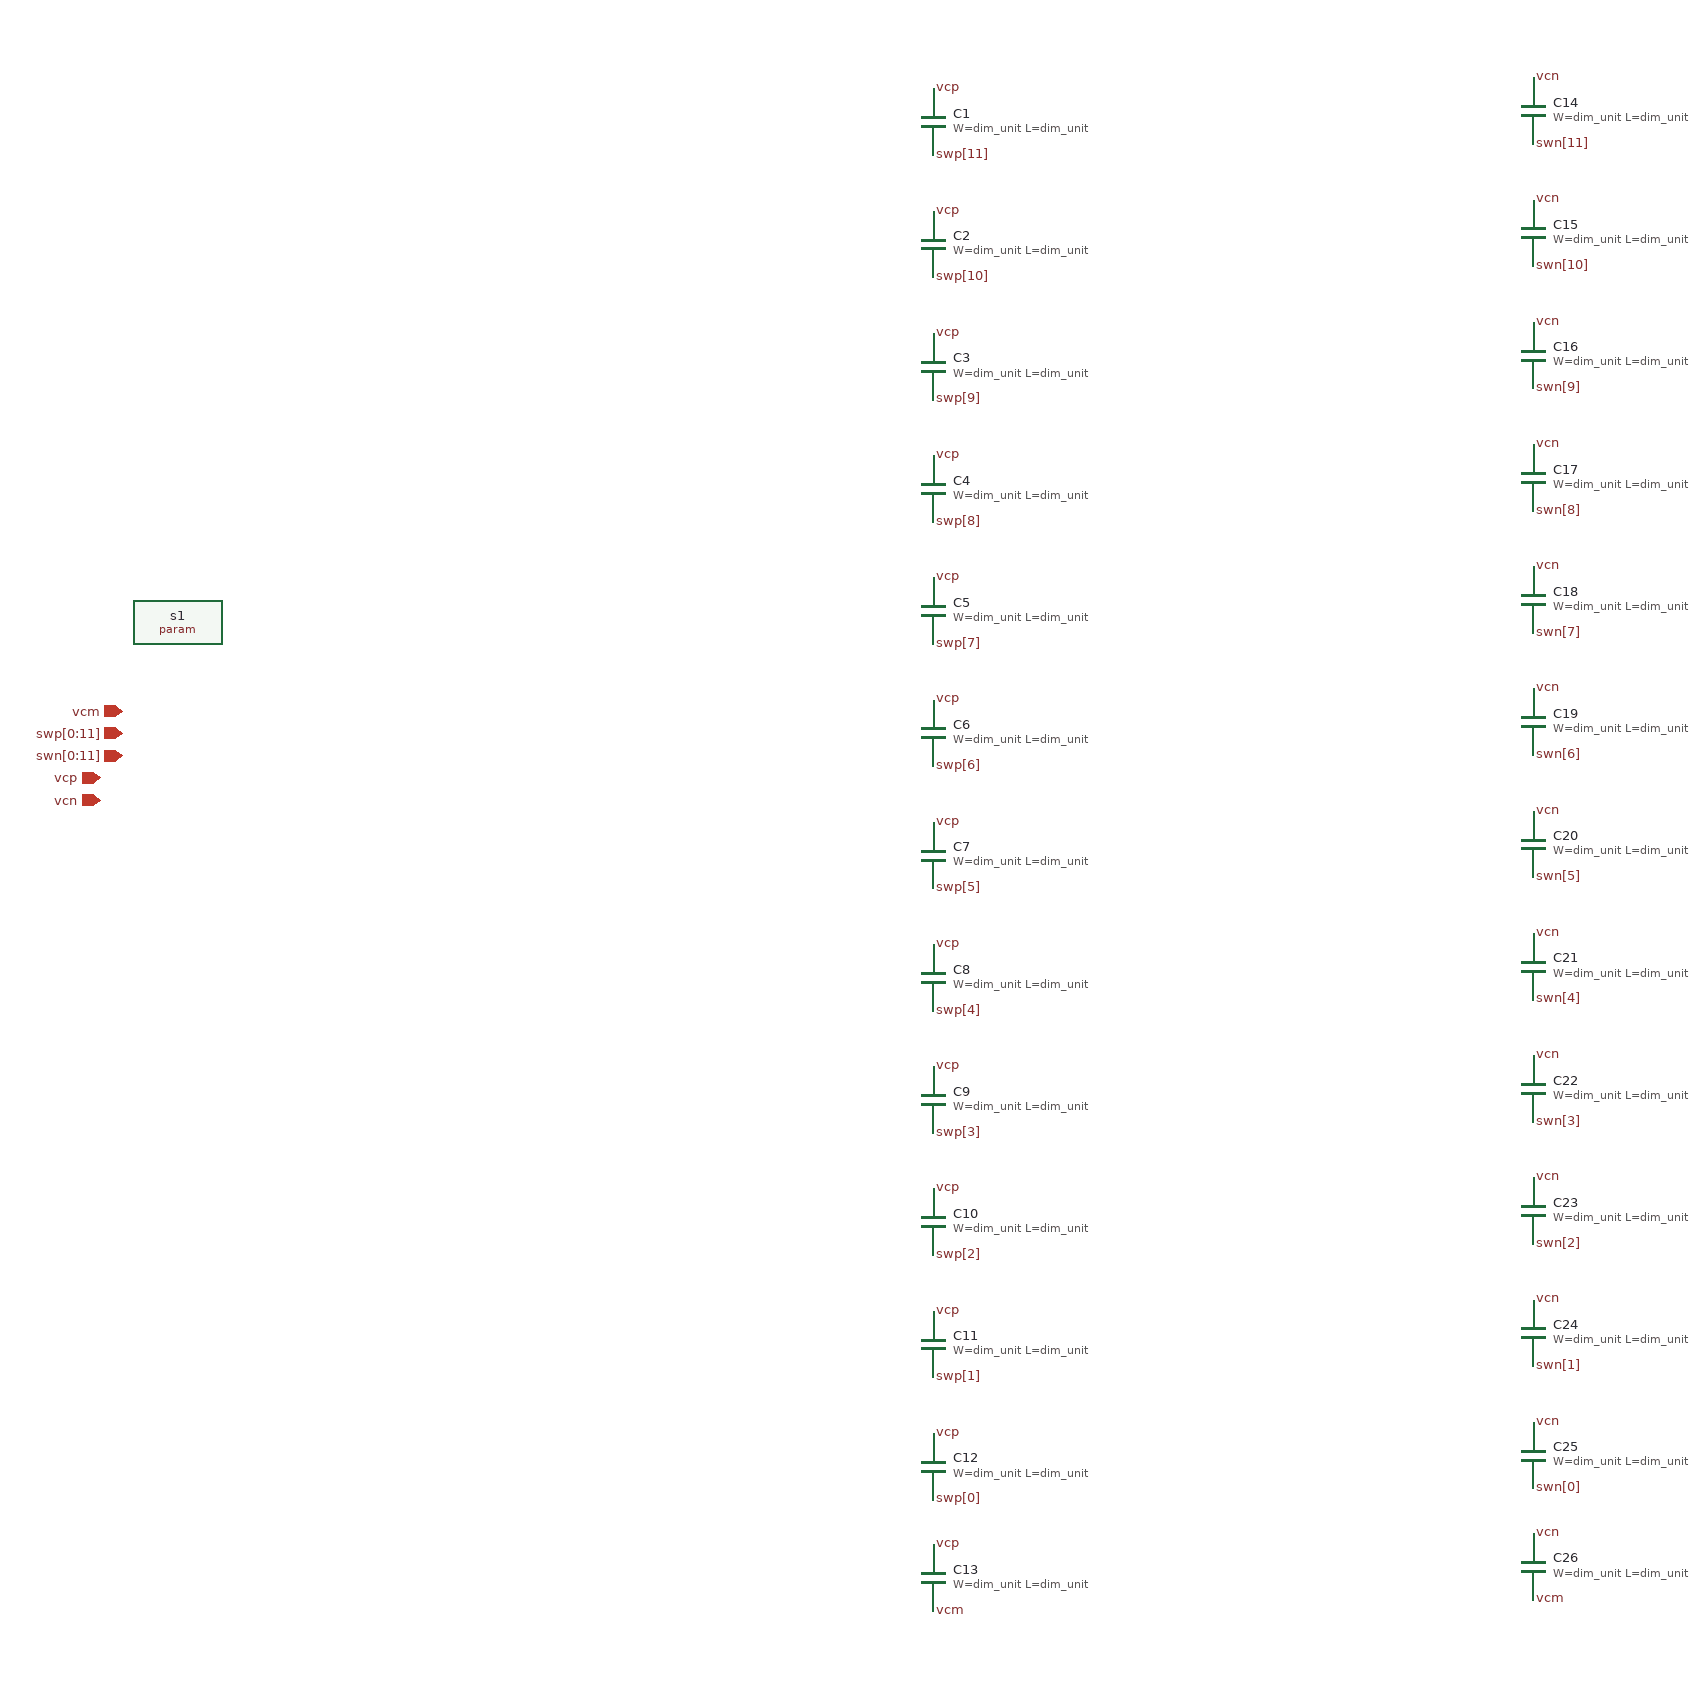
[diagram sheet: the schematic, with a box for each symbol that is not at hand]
v {xschem version=3.4.5 file_version=1.2
}
G {}
K {}
V {}
S {}
E {}
C {devices/lab_wire.sym} 950 -70 2 0 {name=p1 sig_type=std_logic lab=vcm}
C {devices/lab_wire.sym} 950 -170 2 0 {name=p3 sig_type=std_logic lab=swp[0]}
C {devices/lab_wire.sym} 1490 -180 2 0 {name=p4 sig_type=std_logic lab=swn[0]}
C {devices/lab_wire.sym} 950 -280 2 0 {name=p5 sig_type=std_logic lab=swp[1]}
C {devices/lab_wire.sym} 1490 -290 2 0 {name=p6 sig_type=std_logic lab=swn[1]}
C {devices/lab_wire.sym} 950 -390 2 0 {name=p7 sig_type=std_logic lab=swp[2]}
C {devices/lab_wire.sym} 1490 -400 2 0 {name=p8 sig_type=std_logic lab=swn[2]}
C {devices/lab_wire.sym} 950 -500 2 0 {name=p9 sig_type=std_logic lab=swp[3]}
C {devices/lab_wire.sym} 1490 -510 2 0 {name=p10 sig_type=std_logic lab=swn[3]}
C {devices/lab_wire.sym} 950 -610 2 0 {name=p11 sig_type=std_logic lab=swp[4]}
C {devices/lab_wire.sym} 1490 -620 2 0 {name=p12 sig_type=std_logic lab=swn[4]}
C {devices/lab_wire.sym} 950 -720 2 0 {name=p13 sig_type=std_logic lab=swp[5]}
C {devices/lab_wire.sym} 1490 -730 2 0 {name=p14 sig_type=std_logic lab=swn[5]}
C {devices/lab_wire.sym} 950 -830 2 0 {name=p15 sig_type=std_logic lab=swp[6]}
C {devices/lab_wire.sym} 1490 -840 2 0 {name=p16 sig_type=std_logic lab=swn[6]}
C {devices/lab_wire.sym} 950 -940 2 0 {name=p17 sig_type=std_logic lab=swp[7]}
C {devices/lab_wire.sym} 1490 -950 2 0 {name=p18 sig_type=std_logic lab=swn[7]}
C {devices/lab_wire.sym} 950 -1050 2 0 {name=p19 sig_type=std_logic lab=swp[8]}
C {devices/lab_wire.sym} 1490 -1060 2 0 {name=p20 sig_type=std_logic lab=swn[8]}
C {devices/lab_wire.sym} 950 -1160 2 0 {name=p21 sig_type=std_logic lab=swp[9]}
C {devices/lab_wire.sym} 1490 -1170 2 0 {name=p22 sig_type=std_logic lab=swn[9]}
C {devices/lab_wire.sym} 950 -1270 2 0 {name=p23 sig_type=std_logic lab=swp[10]}
C {devices/lab_wire.sym} 1490 -1280 2 0 {name=p24 sig_type=std_logic lab=swn[10]}
C {devices/lab_wire.sym} 950 -1380 2 0 {name=p25 sig_type=std_logic lab=swp[11]}
C {devices/lab_wire.sym} 1490 -1390 2 0 {name=p26 sig_type=std_logic lab=swn[11]}
C {devices/lab_wire.sym} 950 -1440 0 1 {name=p27 sig_type=std_logic lab=vcp}
C {devices/ipin.sym} 220 -860 0 0 {name=p53 lab=swp[0:11]}
C {devices/ipin.sym} 220 -880 0 0 {name=p54 lab=vcm}
C {devices/ipin.sym} 220 -840 0 0 {name=p55 lab=swn[0:11]}
C {devices/iopin.sym} 200 -820 0 0 {name=p56 lab=vcp}
C {devices/iopin.sym} 200 -800 0 0 {name=p57 lab=vcn}
C {devices/param.sym} 270 -960 0 0 {name=s1 value="dim_unit=2u"}
C {sky130_fd_pr/cap_mim_m3_1.sym} 950 -1410 0 0 {name=C1 model=cap_mim_m3_1 W=dim_unit L=dim_unit MF=2048 spiceprefix=X}
C {devices/lab_wire.sym} 950 -1330 0 1 {name=p29 sig_type=std_logic lab=vcp}
C {sky130_fd_pr/cap_mim_m3_1.sym} 950 -1300 0 0 {name=C2 model=cap_mim_m3_1 W=dim_unit L=dim_unit MF=1024 spiceprefix=X}
C {devices/lab_wire.sym} 950 -1220 0 1 {name=p30 sig_type=std_logic lab=vcp}
C {sky130_fd_pr/cap_mim_m3_1.sym} 950 -1190 0 0 {name=C3 model=cap_mim_m3_1 W=dim_unit L=dim_unit MF=512 spiceprefix=X}
C {devices/lab_wire.sym} 950 -1110 0 1 {name=p31 sig_type=std_logic lab=vcp}
C {sky130_fd_pr/cap_mim_m3_1.sym} 950 -1080 0 0 {name=C4 model=cap_mim_m3_1 W=dim_unit L=dim_unit MF=256 spiceprefix=X}
C {devices/lab_wire.sym} 950 -1000 0 1 {name=p32 sig_type=std_logic lab=vcp}
C {sky130_fd_pr/cap_mim_m3_1.sym} 950 -970 0 0 {name=C5 model=cap_mim_m3_1 W=dim_unit L=dim_unit MF=128 spiceprefix=X}
C {devices/lab_wire.sym} 950 -890 0 1 {name=p33 sig_type=std_logic lab=vcp}
C {sky130_fd_pr/cap_mim_m3_1.sym} 950 -860 0 0 {name=C6 model=cap_mim_m3_1 W=dim_unit L=dim_unit MF=64 spiceprefix=X}
C {devices/lab_wire.sym} 950 -780 0 1 {name=p34 sig_type=std_logic lab=vcp}
C {sky130_fd_pr/cap_mim_m3_1.sym} 950 -750 0 0 {name=C7 model=cap_mim_m3_1 W=dim_unit L=dim_unit MF=32 spiceprefix=X}
C {devices/lab_wire.sym} 950 -670 0 1 {name=p35 sig_type=std_logic lab=vcp}
C {sky130_fd_pr/cap_mim_m3_1.sym} 950 -640 0 0 {name=C8 model=cap_mim_m3_1 W=dim_unit L=dim_unit MF=16 spiceprefix=X}
C {devices/lab_wire.sym} 950 -560 0 1 {name=p36 sig_type=std_logic lab=vcp}
C {sky130_fd_pr/cap_mim_m3_1.sym} 950 -530 0 0 {name=C9 model=cap_mim_m3_1 W=dim_unit L=dim_unit MF=8 spiceprefix=X}
C {devices/lab_wire.sym} 950 -450 0 1 {name=p37 sig_type=std_logic lab=vcp}
C {sky130_fd_pr/cap_mim_m3_1.sym} 950 -420 0 0 {name=C10 model=cap_mim_m3_1 W=dim_unit L=dim_unit MF=4 spiceprefix=X}
C {devices/lab_wire.sym} 950 -340 0 1 {name=p38 sig_type=std_logic lab=vcp}
C {sky130_fd_pr/cap_mim_m3_1.sym} 950 -310 0 0 {name=C11 model=cap_mim_m3_1 W=dim_unit L=dim_unit MF=2 spiceprefix=X}
C {devices/lab_wire.sym} 950 -230 0 1 {name=p39 sig_type=std_logic lab=vcp}
C {sky130_fd_pr/cap_mim_m3_1.sym} 950 -200 0 0 {name=C12 model=cap_mim_m3_1 W=dim_unit L=dim_unit MF=1 spiceprefix=X}
C {sky130_fd_pr/cap_mim_m3_1.sym} 950 -100 0 0 {name=C13 model=cap_mim_m3_1 W=dim_unit L=dim_unit MF=1 spiceprefix=X}
C {devices/lab_wire.sym} 1490 -80 2 0 {name=p40 sig_type=std_logic lab=vcm}
C {devices/lab_wire.sym} 1490 -1450 0 1 {name=p58 sig_type=std_logic lab=vcn}
C {sky130_fd_pr/cap_mim_m3_1.sym} 1490 -1420 0 0 {name=C14 model=cap_mim_m3_1 W=dim_unit L=dim_unit MF=2048 spiceprefix=X}
C {devices/lab_wire.sym} 1490 -1340 0 1 {name=p59 sig_type=std_logic lab=vcn}
C {sky130_fd_pr/cap_mim_m3_1.sym} 1490 -1310 0 0 {name=C15 model=cap_mim_m3_1 W=dim_unit L=dim_unit MF=1024 spiceprefix=X}
C {devices/lab_wire.sym} 1490 -1230 0 1 {name=p60 sig_type=std_logic lab=vcn}
C {sky130_fd_pr/cap_mim_m3_1.sym} 1490 -1200 0 0 {name=C16 model=cap_mim_m3_1 W=dim_unit L=dim_unit MF=512 spiceprefix=X}
C {devices/lab_wire.sym} 1490 -1120 0 1 {name=p61 sig_type=std_logic lab=vcn}
C {sky130_fd_pr/cap_mim_m3_1.sym} 1490 -1090 0 0 {name=C17 model=cap_mim_m3_1 W=dim_unit L=dim_unit MF=256 spiceprefix=X}
C {devices/lab_wire.sym} 1490 -1010 0 1 {name=p62 sig_type=std_logic lab=vcn}
C {sky130_fd_pr/cap_mim_m3_1.sym} 1490 -980 0 0 {name=C18 model=cap_mim_m3_1 W=dim_unit L=dim_unit MF=128 spiceprefix=X}
C {devices/lab_wire.sym} 1490 -900 0 1 {name=p63 sig_type=std_logic lab=vcn}
C {sky130_fd_pr/cap_mim_m3_1.sym} 1490 -870 0 0 {name=C19 model=cap_mim_m3_1 W=dim_unit L=dim_unit MF=64 spiceprefix=X}
C {devices/lab_wire.sym} 1490 -790 0 1 {name=p64 sig_type=std_logic lab=vcn}
C {sky130_fd_pr/cap_mim_m3_1.sym} 1490 -760 0 0 {name=C20 model=cap_mim_m3_1 W=dim_unit L=dim_unit MF=32 spiceprefix=X}
C {devices/lab_wire.sym} 1490 -680 0 1 {name=p65 sig_type=std_logic lab=vcn}
C {sky130_fd_pr/cap_mim_m3_1.sym} 1490 -650 0 0 {name=C21 model=cap_mim_m3_1 W=dim_unit L=dim_unit MF=16 spiceprefix=X}
C {devices/lab_wire.sym} 1490 -570 0 1 {name=p66 sig_type=std_logic lab=vcn}
C {sky130_fd_pr/cap_mim_m3_1.sym} 1490 -540 0 0 {name=C22 model=cap_mim_m3_1 W=dim_unit L=dim_unit MF=8 spiceprefix=X}
C {devices/lab_wire.sym} 1490 -460 0 1 {name=p67 sig_type=std_logic lab=vcn}
C {sky130_fd_pr/cap_mim_m3_1.sym} 1490 -430 0 0 {name=C23 model=cap_mim_m3_1 W=dim_unit L=dim_unit MF=4 spiceprefix=X}
C {devices/lab_wire.sym} 1490 -350 0 1 {name=p68 sig_type=std_logic lab=vcn}
C {sky130_fd_pr/cap_mim_m3_1.sym} 1490 -320 0 0 {name=C24 model=cap_mim_m3_1 W=dim_unit L=dim_unit MF=2 spiceprefix=X}
C {devices/lab_wire.sym} 1490 -240 0 1 {name=p69 sig_type=std_logic lab=vcn}
C {sky130_fd_pr/cap_mim_m3_1.sym} 1490 -210 0 0 {name=C25 model=cap_mim_m3_1 W=dim_unit L=dim_unit MF=1 spiceprefix=X}
C {sky130_fd_pr/cap_mim_m3_1.sym} 1490 -110 0 0 {name=C26 model=cap_mim_m3_1 W=dim_unit L=dim_unit MF=1 spiceprefix=X}
C {devices/lab_wire.sym} 1490 -140 0 1 {name=p70 sig_type=std_logic lab=vcn}
C {devices/lab_wire.sym} 950 -130 0 1 {name=p71 sig_type=std_logic lab=vcp}
